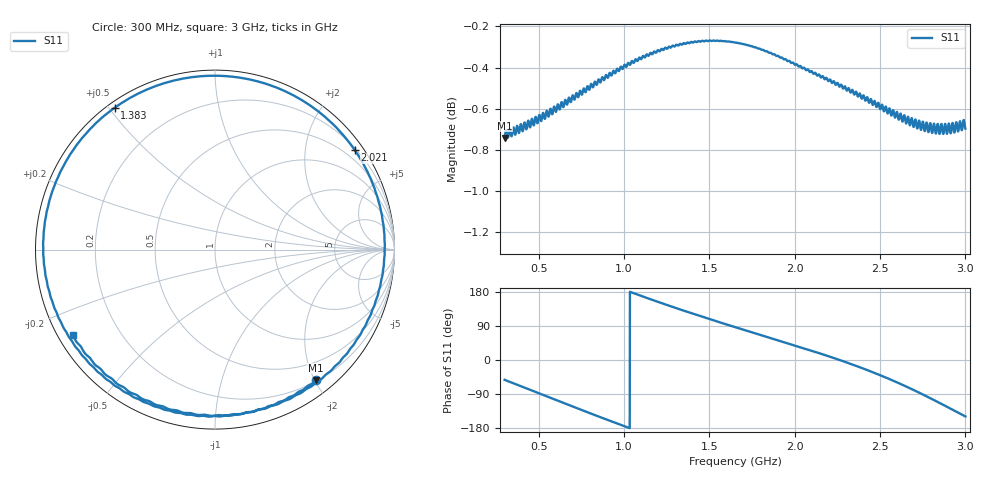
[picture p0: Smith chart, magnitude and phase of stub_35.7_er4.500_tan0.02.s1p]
! Chirptenna · simulación 3D de un stub abierto
# HZ S RI R 50
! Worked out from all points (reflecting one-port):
!   2001 points, 300 MHz to 3 GHz, reference 50 ohm
!   lowest |S11| = -0.7 dB at 300 MHz (marker M1), VSWR 23.44, Z = 10.9 - j101 ohm
!   phase of S11 starts at -52 deg and turns -457 deg over the sweep
!   S11 on the Smith chart (normalised r, x): 300 MHz: 0.22, -2.02; 1.383 GHz: 0.02, +0.52; 2.021 GHz: 0.24, +3.12; 3 GHz: 0.04, -0.28
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3e8  0.5616 -0.7263
3.864e8  0.3527 -0.8509
4.7145e8  0.12 -0.9168
5.565e8  -0.1231 -0.921
6.375e8  -0.3498 -0.8682
7.2795e8  -0.576 -0.7424
8.1975e8  -0.7611 -0.5597
9.0345e8  -0.881 -0.3542
9.75e8  -0.94 -0.1638
1.056e9  -0.9556 0.0605
1.1397e9  -0.9183 0.2848
1.3125e9  -0.693 0.6744
1.3827e9  -0.5585 0.7907
1.515e9  -0.2653 0.9323
1.65e9  0.0548 0.9669
1.812e9  0.4179 0.8693
1.9875e9  0.7325 0.617
2.02125e9  0.7792 0.5532
2.17785e9  0.9249 0.2117
2.325e9  0.9279 -0.162
2.41275e9  0.853 -0.3891
2.49645e9  0.7213 -0.5937
2.58285e9  0.5213 -0.7705
2.6625e9  0.2878 -0.8833
2.7408e9  0.019 -0.9221
2.82585e9  -0.2862 -0.8748
2.90955e9  -0.5648 -0.7291
3e9  -0.7909 -0.4757
